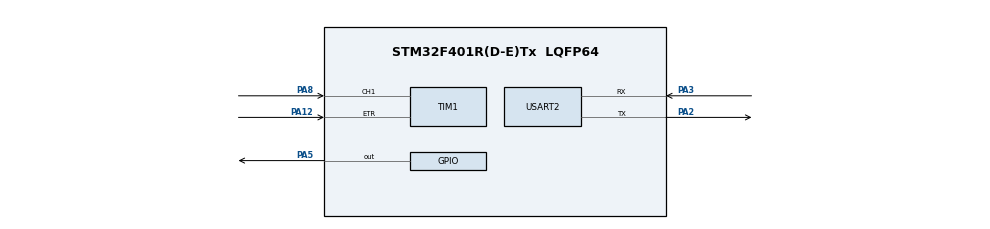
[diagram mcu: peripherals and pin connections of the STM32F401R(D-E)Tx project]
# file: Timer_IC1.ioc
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Mcu.Family=STM32F4
Mcu.Name=STM32F401R(D-E)Tx
Mcu.Package=LQFP64
NVIC.PriorityGroup=NVIC_PRIORITYGROUP_4
NVIC.TIM1_CC_IRQn=true\:0\:0\:false\:false\:true\:true\:true
PA12.Signal=S_TIM1_ETR
PA13.Mode=Serial_Wire
PA13.Signal=SYS_JTMS-SWDIO
PA14.Mode=Serial_Wire
PA14.Signal=SYS_JTCK-SWCLK
PA2.Mode=Asynchronous
PA2.Signal=USART2_TX
PA3.Mode=Asynchronous
PA3.Signal=USART2_RX
PA5.Signal=GPIO_Output
PA8.Signal=S_TIM1_CH1
PC14-OSC32_IN.Mode=LSE-External-Oscillator
PC14-OSC32_IN.Signal=RCC_OSC32_IN
PC15-OSC32_OUT.Mode=LSE-External-Oscillator
PC15-OSC32_OUT.Signal=RCC_OSC32_OUT
ProjectManager.HeapSize=0x200
ProjectManager.StackSize=0x400
ProjectManager.TargetToolchain=STM32CubeIDE
RCC.48MHZClocksFreq_Value=42000000
RCC.AHBFreq_Value=84000000
RCC.APB1CLKDivider=RCC_HCLK_DIV16
RCC.APB1Freq_Value=5250000
RCC.APB1TimFreq_Value=10500000
RCC.APB2Freq_Value=84000000
RCC.APB2TimFreq_Value=84000000
RCC.CortexFreq_Value=10500000
RCC.Cortex_Div=SYSTICK_CLKSOURCE_HCLK_DIV8
RCC.HCLKFreq_Value=84000000
RCC.HSE_VALUE=25000000
RCC.HSI_VALUE=16000000
RCC.PLLM=8
RCC.PLLN=84
RCC.SYSCLKFreq_VALUE=84000000
RCC.SYSCLKSource=RCC_SYSCLKSOURCE_PLLCLK
RCC.VCOOutputFreq_Value=168000000
SH.S_TIM1_CH1.0=TIM1_CH1,Input_Capture1_from_TI1
SH.S_TIM1_ETR.0=TIM1_ETR,ClockSourceETR_Mode2
TIM1.Channel-Input_Capture1_from_TI1=TIM_CHANNEL_1
USART2.VirtualMode=VM_ASYNC
board=custom

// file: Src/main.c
/* USER CODE BEGIN Header */
/**
  ******************************************************************************
  * @file           : main.c
  * @brief          : Main program body
  ******************************************************************************
  * @attention
  *
  * <h2><center>&copy; Copyright (c) 2021 STMicroelectronics.
  * All rights reserved.</center></h2>
  *
  * This software component is licensed by ST under BSD 3-Clause license,
  * the "License"; You may not use this file except in compliance with the
  * License. You may obtain a copy of the License at:
  *                        opensource.org/licenses/BSD-3-Clause
  *
  ******************************************************************************
  */
/* USER CODE END Header */
#include "main.h"

TIM_HandleTypeDef htim1;

UART_HandleTypeDef huart2;

void SystemClock_Config(void);
static void MX_GPIO_Init(void);
static void MX_TIM1_Init(void);
static void MX_USART2_UART_Init(void);

/* USER CODE BEGIN 0 */
long buff[50];

/* USER CODE END 0 */

int main(void)
{

  /* MCU Configuration--------------------------------------------------------*/

  /* Reset of all peripherals, Initializes the Flash interface and the Systick. */
  HAL_Init();

  /* Configure the system clock */
  SystemClock_Config();

  /* Initialize all configured peripherals */
  MX_GPIO_Init();
  MX_TIM1_Init();
  MX_USART2_UART_Init();
  /* USER CODE BEGIN 2 */

 // memset(buff,0,sizeof(buff));
  sprintf(buff, "HCLK = %ld Hz   LSI\r\n", HAL_RCC_GetSysClockFreq() );

  if(HAL_UART_Transmit(&huart2, &buff, strlen(buff), HAL_MAX_DELAY)!=HAL_OK){
	  Error_Handler();
  }

  /* USER CODE END 2 */

  /* Infinite loop */
  /* USER CODE BEGIN WHILE */
  while (1)
  {

  }
  /* USER CODE END 3 */
}

void SystemClock_Config(void)
{
  RCC_OscInitTypeDef RCC_OscInitStruct = {0};
  RCC_ClkInitTypeDef RCC_ClkInitStruct = {0};

  /** Configure the main internal regulator output voltage
  */
  __HAL_RCC_PWR_CLK_ENABLE();
  __HAL_PWR_VOLTAGESCALING_CONFIG(PWR_REGULATOR_VOLTAGE_SCALE2);
  /** Initializes the RCC Oscillators according to the specified parameters
  * in the RCC_OscInitTypeDef structure.
  */
  RCC_OscInitStruct.OscillatorType = RCC_OSCILLATORTYPE_HSI| RCC_OSCILLATORTYPE_LSE;
  RCC_OscInitStruct.HSIState = RCC_HSI_ON;
  RCC_OscInitStruct.HSEState = RCC_HSE_ON;
  RCC_OscInitStruct.HSICalibrationValue = RCC_HSICALIBRATION_DEFAULT;
  RCC_OscInitStruct.PLL.PLLState = RCC_PLL_ON;
  RCC_OscInitStruct.PLL.PLLSource = RCC_PLLSOURCE_HSI;
  RCC_OscInitStruct.PLL.PLLM = 8;
  RCC_OscInitStruct.PLL.PLLN = 50;
  RCC_OscInitStruct.PLL.PLLP = RCC_PLLP_DIV2;
  RCC_OscInitStruct.PLL.PLLQ = 4;
  if (HAL_RCC_OscConfig(&RCC_OscInitStruct) != HAL_OK)
  {
    Error_Handler();
  }
  /** Initializes the CPU, AHB and APB buses clocks
  */
  RCC_ClkInitStruct.ClockType = RCC_CLOCKTYPE_HCLK|RCC_CLOCKTYPE_SYSCLK
                              |RCC_CLOCKTYPE_PCLK1|RCC_CLOCKTYPE_PCLK2;
  RCC_ClkInitStruct.SYSCLKSource = RCC_SYSCLKSOURCE_PLLCLK;
  RCC_ClkInitStruct.AHBCLKDivider = RCC_SYSCLK_DIV1;
  RCC_ClkInitStruct.APB1CLKDivider = RCC_HCLK_DIV2;
  RCC_ClkInitStruct.APB2CLKDivider = RCC_HCLK_DIV1;

  if (HAL_RCC_ClockConfig(&RCC_ClkInitStruct, FLASH_LATENCY_1) != HAL_OK)
  {
    Error_Handler();
  }

  HAL_RCC_MCOConfig(RCC_MCO1,RCC_MCO1SOURCE_HSI,RCC_MCODIV_4);
}

static void MX_TIM1_Init(void)
{

  TIM_ClockConfigTypeDef sClockSourceConfig = {0};
  TIM_MasterConfigTypeDef sMasterConfig = {0};
  TIM_IC_InitTypeDef sConfigIC = {0};

  htim1.Instance = TIM1;
  htim1.Init.Prescaler = 0;
  htim1.Init.CounterMode = TIM_COUNTERMODE_UP;
  htim1.Init.Period = 65535;
  htim1.Init.ClockDivision = TIM_CLOCKDIVISION_DIV1;
  htim1.Init.RepetitionCounter = 0;
  htim1.Init.AutoReloadPreload = TIM_AUTORELOAD_PRELOAD_DISABLE;
  if (HAL_TIM_Base_Init(&htim1) != HAL_OK)
  {
    Error_Handler();
  }
  sClockSourceConfig.ClockSource = TIM_CLOCKSOURCE_ETRMODE2;
  sClockSourceConfig.ClockPolarity = TIM_CLOCKPOLARITY_NONINVERTED;
  sClockSourceConfig.ClockPrescaler = TIM_CLOCKPRESCALER_DIV1;
  sClockSourceConfig.ClockFilter = 0;
  if (HAL_TIM_ConfigClockSource(&htim1, &sClockSourceConfig) != HAL_OK)
  {
    Error_Handler();
  }
  if (HAL_TIM_IC_Init(&htim1) != HAL_OK)
  {
    Error_Handler();
  }
  sMasterConfig.MasterOutputTrigger = TIM_TRGO_RESET;
  sMasterConfig.MasterSlaveMode = TIM_MASTERSLAVEMODE_DISABLE;
  if (HAL_TIMEx_MasterConfigSynchronization(&htim1, &sMasterConfig) != HAL_OK)
  {
    Error_Handler();
  }
  sConfigIC.ICPolarity = TIM_INPUTCHANNELPOLARITY_RISING;
  sConfigIC.ICSelection = TIM_ICSELECTION_DIRECTTI;
  sConfigIC.ICPrescaler = TIM_ICPSC_DIV1;
  sConfigIC.ICFilter = 0;
  if (HAL_TIM_IC_ConfigChannel(&htim1, &sConfigIC, TIM_CHANNEL_1) != HAL_OK)
  {
    Error_Handler();
  }

}

static void MX_USART2_UART_Init(void)
{

  huart2.Instance = USART2;
  huart2.Init.BaudRate = 115200;
  huart2.Init.WordLength = UART_WORDLENGTH_8B;
  huart2.Init.StopBits = UART_STOPBITS_1;
  huart2.Init.Parity = UART_PARITY_NONE;
  huart2.Init.Mode = UART_MODE_TX_RX;
  huart2.Init.HwFlowCtl = UART_HWCONTROL_NONE;
  huart2.Init.OverSampling = UART_OVERSAMPLING_16;
  if (HAL_UART_Init(&huart2) != HAL_OK)
  {
    Error_Handler();
  }

}

static void MX_GPIO_Init(void)
{
  GPIO_InitTypeDef GPIO_InitStruct = {0};

  /* GPIO Ports Clock Enable */
  __HAL_RCC_GPIOC_CLK_ENABLE();
  __HAL_RCC_GPIOA_CLK_ENABLE();

  /*Configure GPIO pin Output Level */
  HAL_GPIO_WritePin(GPIOA, GPIO_PIN_5, GPIO_PIN_RESET);

  /*Configure GPIO pin : PA5 */
  GPIO_InitStruct.Pin = GPIO_PIN_5;
  GPIO_InitStruct.Mode = GPIO_MODE_OUTPUT_PP;
  GPIO_InitStruct.Pull = GPIO_NOPULL;
  GPIO_InitStruct.Speed = GPIO_SPEED_FREQ_LOW;
  HAL_GPIO_Init(GPIOA, &GPIO_InitStruct);

}

void Error_Handler(void)
{
  __disable_irq();
  while (1)
  {
  }
}

/************************ (C) COPYRIGHT STMicroelectronics *****END OF FILE****/
